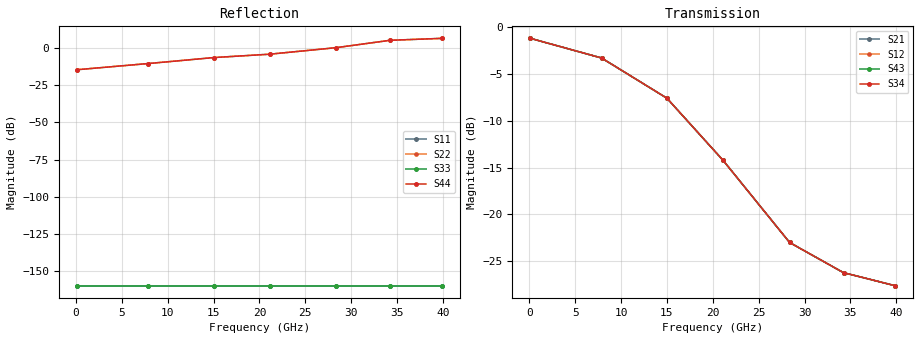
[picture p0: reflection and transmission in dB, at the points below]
! 26-Jun-2017 15:41:54
# Hz S RI R 50
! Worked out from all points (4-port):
!   319 points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, 125 MHz to 39.88 GHz, reference 50 ohm
!   strongest paths, dB at 125 MHz, 10 GHz, 20 GHz, 30 GHz, 39.88 GHz:
!     S43: -1.2, -4.1, -12.9, -24.4, -27.6
!     S21: -1.2, -4.1, -12.9, -24.4, -27.6
!     S42: -, -, -, -, -
!     S41: -, -, -, -, -
!     S32: -, -, -, -, -
!     S31: -, -, -, -, -
!   lowest |S11| = - dB at 125 MHz (marker M1), VSWR 1.00, Z = 50 + j0 ohm
!   |S11| at or under -10 dB: start of sweep to end of sweep
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1.25e8  0 0  0.8716 -0.0206  0 0  0 0
        0.8716 -0.0206  -0.1898 -0.00446  0 0  0 0
        0 0  0 0  0 0  0.8716 -0.0206
        0 0  0 0  0.8716 -0.0206  -0.1898 -0.00446
7.875e9  0 0  0.2792 -0.6252  0 0  0 0
         0.2792 -0.6252  -0.3053 0.0236  0 0  0 0
         0 0  0 0  0 0  0.2792 -0.6252
         0 0  0 0  0.2792 -0.6252  -0.3053 0.0236
1.5e10  0 0  -0.271 -0.3176  0 0  0 0
        -0.271 -0.3176  -0.4743 0.108  0 0  0 0
        0 0  0 0  0 0  -0.271 -0.3176
        0 0  0 0  -0.271 -0.3176  -0.4743 0.108
2.1125e10  0 0  -0.1928 0.0234  0 0  0 0
           -0.1928 0.0234  -0.4955 0.3936  0 0  0 0
           0 0  0 0  0 0  -0.1928 0.0234
           0 0  0 0  -0.1928 0.0234  -0.4955 0.3936
2.8375e10  0 0  0.00086 0.0707  0 0  0 0
           0.00086 0.0707  -0.3083 1.005  0 0  0 0
           0 0  0 0  0 0  0.00086 0.0707
           0 0  0 0  0.00086 0.0707  -0.3083 1.005
3.425e10  0 0  0.047 0.013  0 0  0 0
          0.047 0.013  -0.5493 1.778  0 0  0 0
          0 0  0 0  0 0  0.047 0.013
          0 0  0 0  0.047 0.013  -0.5493 1.778
3.9875e10  0 0  0.0315 -0.0271  0 0  0 0
           0.0315 -0.0271  -0.7748 2.016  0 0  0 0
           0 0  0 0  0 0  0.0315 -0.0271
           0 0  0 0  0.0315 -0.0271  -0.7748 2.016
